One B-rep face of a CAD part: STEP entity #66634.
In plain terms, the planar face has unit normal (0, 1, 0).
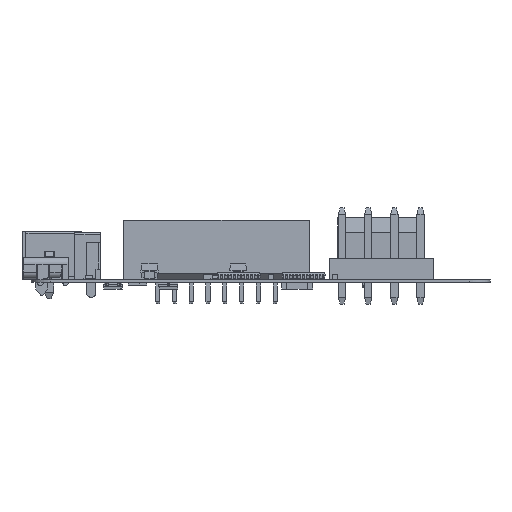
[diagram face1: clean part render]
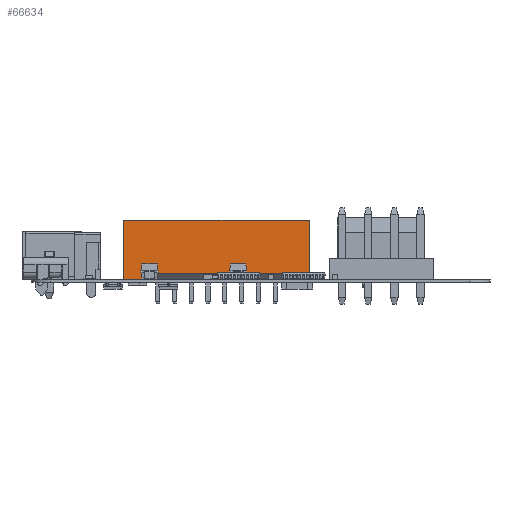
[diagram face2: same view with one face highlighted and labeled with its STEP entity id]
Its self-contained STEP definition (entity closure, numbers rounded to 3 decimals):
#66634 = ADVANCED_FACE('',(#66635),#66701,.T.);
#66635 = FACE_BOUND('',#66636,.T.);
#66636 = EDGE_LOOP('',(#66637,#66647,#66655,#66663,#66671,#66679,#66687,
    #66695));
#66637 = ORIENTED_EDGE('',*,*,#66638,.T.);
#66638 = EDGE_CURVE('',#66639,#66641,#66643,.T.);
#66639 = VERTEX_POINT('',#66640);
#66640 = CARTESIAN_POINT('',(22.95,5.67,0.));
#66641 = VERTEX_POINT('',#66642);
#66642 = CARTESIAN_POINT('',(19.05,5.67,0.));
#66643 = LINE('',#66644,#66645);
#66644 = CARTESIAN_POINT('',(1.27,5.67,0.));
#66645 = VECTOR('',#66646,1.);
#66646 = DIRECTION('',(-1.,0.,0.));
#66647 = ORIENTED_EDGE('',*,*,#66648,.T.);
#66648 = EDGE_CURVE('',#66641,#66649,#66651,.T.);
#66649 = VERTEX_POINT('',#66650);
#66650 = CARTESIAN_POINT('',(19.05,5.67,1.));
#66651 = LINE('',#66652,#66653);
#66652 = CARTESIAN_POINT('',(19.05,5.67,0.));
#66653 = VECTOR('',#66654,1.);
#66654 = DIRECTION('',(0.,0.,1.));
#66655 = ORIENTED_EDGE('',*,*,#66656,.T.);
#66656 = EDGE_CURVE('',#66649,#66657,#66659,.T.);
#66657 = VERTEX_POINT('',#66658);
#66658 = CARTESIAN_POINT('',(-1.27,5.67,1.));
#66659 = LINE('',#66660,#66661);
#66660 = CARTESIAN_POINT('',(1.27,5.67,1.));
#66661 = VECTOR('',#66662,1.);
#66662 = DIRECTION('',(-1.,0.,0.));
#66663 = ORIENTED_EDGE('',*,*,#66664,.T.);
#66664 = EDGE_CURVE('',#66657,#66665,#66667,.T.);
#66665 = VERTEX_POINT('',#66666);
#66666 = CARTESIAN_POINT('',(-1.27,5.67,0.));
#66667 = LINE('',#66668,#66669);
#66668 = CARTESIAN_POINT('',(-1.27,5.67,0.));
#66669 = VECTOR('',#66670,1.);
#66670 = DIRECTION('',(0.,0.,-1.));
#66671 = ORIENTED_EDGE('',*,*,#66672,.T.);
#66672 = EDGE_CURVE('',#66665,#66673,#66675,.T.);
#66673 = VERTEX_POINT('',#66674);
#66674 = CARTESIAN_POINT('',(-5.17,5.67,0.));
#66675 = LINE('',#66676,#66677);
#66676 = CARTESIAN_POINT('',(1.27,5.67,0.));
#66677 = VECTOR('',#66678,1.);
#66678 = DIRECTION('',(-1.,0.,0.));
#66679 = ORIENTED_EDGE('',*,*,#66680,.T.);
#66680 = EDGE_CURVE('',#66673,#66681,#66683,.T.);
#66681 = VERTEX_POINT('',#66682);
#66682 = CARTESIAN_POINT('',(-5.17,5.67,9.));
#66683 = LINE('',#66684,#66685);
#66684 = CARTESIAN_POINT('',(-5.17,5.67,0.));
#66685 = VECTOR('',#66686,1.);
#66686 = DIRECTION('',(0.,0.,1.));
#66687 = ORIENTED_EDGE('',*,*,#66688,.T.);
#66688 = EDGE_CURVE('',#66681,#66689,#66691,.T.);
#66689 = VERTEX_POINT('',#66690);
#66690 = CARTESIAN_POINT('',(22.95,5.67,9.));
#66691 = LINE('',#66692,#66693);
#66692 = CARTESIAN_POINT('',(1.27,5.67,9.));
#66693 = VECTOR('',#66694,1.);
#66694 = DIRECTION('',(1.,0.,0.));
#66695 = ORIENTED_EDGE('',*,*,#66696,.T.);
#66696 = EDGE_CURVE('',#66689,#66639,#66697,.T.);
#66697 = LINE('',#66698,#66699);
#66698 = CARTESIAN_POINT('',(22.95,5.67,0.));
#66699 = VECTOR('',#66700,1.);
#66700 = DIRECTION('',(0.,0.,-1.));
#66701 = PLANE('',#66702);
#66702 = AXIS2_PLACEMENT_3D('',#66703,#66704,#66705);
#66703 = CARTESIAN_POINT('',(1.27,5.67,0.));
#66704 = DIRECTION('',(0.,1.,0.));
#66705 = DIRECTION('',(0.,0.,1.));
